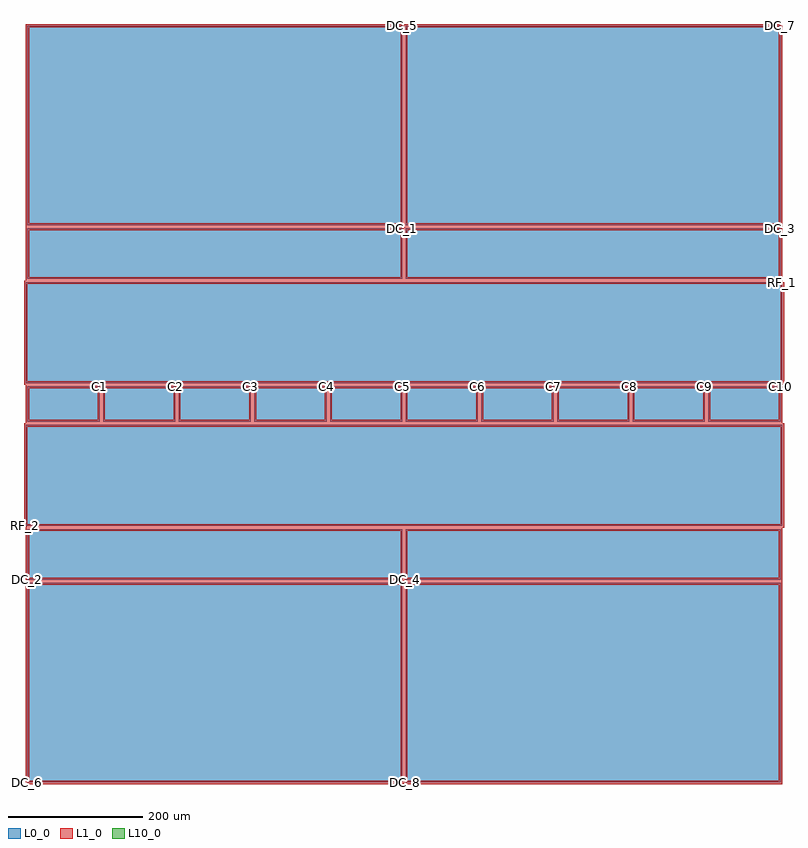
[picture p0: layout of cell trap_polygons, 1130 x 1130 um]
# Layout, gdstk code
import gdstk
lib = gdstk.Library(unit=1e-6, precision=1e-09)
def P(c, l, *ps):  # polygons
    for p in ps: c.add(gdstk.Polygon(p, *l))
L0_0 = (0, 0)
L1_0 = (1, 0)
L10_0 = (10, 0)

trap_polygons = lib.new_cell('trap_polygons')
P(trap_polygons, L0_0, [(2.5,-562.5),(2.5,-266.125),(560,-266.125),(560,-562.5),(2.5,-562.5)],
  [(560,562.5),(560,266.125),(2.5,266.125),(2.5,562.5),(560,562.5)],
  [(-560,-562.5),(-560,-266.125),(-2.5,-266.125),(-2.5,-562.5),(-560,-562.5)],
  [(-2.5,562.5),(-2.5,266.125),(-560,266.125),(-560,562.5),(-2.5,562.5)],
  [(2.5,-261.125),(2.5,-186.125),(560,-186.125),(560,-261.125),(2.5,-261.125)],
  [(560,261.125),(560,186.125),(2.5,186.125),(2.5,261.125),(560,261.125)],
  [(-560,-261.125),(-560,-186.125),(-2.5,-186.125),(-2.5,-261.125),(-560,-261.125)],
  [(-2.5,261.125),(-2.5,186.125),(-560,186.125),(-560,261.125),(-2.5,261.125)],
  [(560,26.125),(560,-26.125),(452.5,-26.125),(452.5,26.125),(560,26.125)],
  [(447.5,26.125),(447.5,-26.125),(340,-26.125),(340,26.125),(447.5,26.125)],
  [(335,26.125),(335,-26.125),(227.5,-26.125),(227.5,26.125),(335,26.125)],
  [(222.5,26.125),(222.5,-26.125),(115,-26.125),(115,26.125),(222.5,26.125)],
  [(110,26.125),(110,-26.125),(2.5,-26.125),(2.5,26.125),(110,26.125)],
  [(-2.5,26.125),(-2.5,-26.125),(-110,-26.125),(-110,26.125),(-2.5,26.125)],
  [(-115,26.125),(-115,-26.125),(-222.5,-26.125),(-222.5,26.125),(-115,26.125)],
  [(-227.5,26.125),(-227.5,-26.125),(-335,-26.125),(-335,26.125),(-227.5,26.125)],
  [(-340,26.125),(-340,-26.125),(-447.5,-26.125),(-447.5,26.125),(-340,26.125)],
  [(-452.5,26.125),(-452.5,-26.125),(-560,-26.125),(-560,26.125),(-452.5,26.125)],
  [(-562.5,-181.125),(-562.5,-31.125),(562.5,-31.125),(562.5,-181.125),(-562.5,-181.125)],
  [(562.5,181.125),(562.5,31.125),(-562.5,31.125),(-562.5,181.125),(562.5,181.125)])
P(trap_polygons, L1_0, [(0,-562.5),(5,-562.5),(5,-268.625),(557.5,-268.625),(557.5,-560),(2.5,-560),(2.5,-565),(562.5,-565),(562.5,-263.625),(0,-263.625)],
  [(562.5,562.5),(557.5,562.5),(557.5,268.625),(5,268.625),(5,560),(560,560),(560,565),(0,565),(0,263.625),(562.5,263.625)],
  [(-562.5,-562.5),(-557.5,-562.5),(-557.5,-268.625),(-5,-268.625),(-5,-560),(-560,-560),(-560,-565),(0,-565),(0,-263.625),(-562.5,-263.625)],
  [(0,562.5),(-5,562.5),(-5,268.625),(-557.5,268.625),(-557.5,560),(-2.5,560),(-2.5,565),(-562.5,565),(-562.5,263.625),(0,263.625)],
  [(0,-261.125),(5,-261.125),(5,-188.625),(557.5,-188.625),(557.5,-258.625),(2.5,-258.625),(2.5,-263.625),(562.5,-263.625),(562.5,-183.625),(0,-183.625)],
  [(562.5,261.125),(557.5,261.125),(557.5,188.625),(5,188.625),(5,258.625),(560,258.625),(560,263.625),(0,263.625),(0,183.625),(562.5,183.625)],
  [(-562.5,-261.125),(-557.5,-261.125),(-557.5,-188.625),(-5,-188.625),(-5,-258.625),(-560,-258.625),(-560,-263.625),(0,-263.625),(0,-183.625),(-562.5,-183.625)],
  [(0,261.125),(-5,261.125),(-5,188.625),(-557.5,188.625),(-557.5,258.625),(-2.5,258.625),(-2.5,263.625),(-562.5,263.625),(-562.5,183.625),(0,183.625)],
  [(562.5,26.125),(557.5,26.125),(557.5,-23.625),(455,-23.625),(455,23.625),(560,23.625),(560,28.625),(450,28.625),(450,-28.625),(562.5,-28.625)],
  [(450,26.125),(445,26.125),(445,-23.625),(342.5,-23.625),(342.5,23.625),(447.5,23.625),(447.5,28.625),(337.5,28.625),(337.5,-28.625),(450,-28.625)],
  [(337.5,26.125),(332.5,26.125),(332.5,-23.625),(230,-23.625),(230,23.625),(335,23.625),(335,28.625),(225,28.625),(225,-28.625),(337.5,-28.625)],
  [(225,26.125),(220,26.125),(220,-23.625),(117.5,-23.625),(117.5,23.625),(222.5,23.625),(222.5,28.625),(112.5,28.625),(112.5,-28.625),(225,-28.625)],
  [(112.5,26.125),(107.5,26.125),(107.5,-23.625),(5,-23.625),(5,23.625),(110,23.625),(110,28.625),(0,28.625),(0,-28.625),(112.5,-28.625)],
  [(0,26.125),(-5,26.125),(-5,-23.625),(-107.5,-23.625),(-107.5,23.625),(-2.5,23.625),(-2.5,28.625),(-112.5,28.625),(-112.5,-28.625),(0,-28.625)],
  [(-112.5,26.125),(-117.5,26.125),(-117.5,-23.625),(-220,-23.625),(-220,23.625),(-115,23.625),(-115,28.625),(-225,28.625),(-225,-28.625),(-112.5,-28.625)],
  [(-225,26.125),(-230,26.125),(-230,-23.625),(-332.5,-23.625),(-332.5,23.625),(-227.5,23.625),(-227.5,28.625),(-337.5,28.625),(-337.5,-28.625),(-225,-28.625)],
  [(-337.5,26.125),(-342.5,26.125),(-342.5,-23.625),(-445,-23.625),(-445,23.625),(-340,23.625),(-340,28.625),(-450,28.625),(-450,-28.625),(-337.5,-28.625)],
  [(-450,26.125),(-455,26.125),(-455,-23.625),(-557.5,-23.625),(-557.5,23.625),(-452.5,23.625),(-452.5,28.625),(-562.5,28.625),(-562.5,-28.625),(-450,-28.625)],
  [(-565,-181.125),(-560,-181.125),(-560,-33.625),(560,-33.625),(560,-178.625),(-562.5,-178.625),(-562.5,-183.625),(565,-183.625),(565,-28.625),(-565,-28.625)],
  [(565,181.125),(560,181.125),(560,33.625),(-560,33.625),(-560,178.625),(562.5,178.625),(562.5,183.625),(-565,183.625),(-565,28.625),(565,28.625)])
P(trap_polygons, L10_0, [(0,0),(0,0),(0,0),(0,0)])
trap_polygons.add(gdstk.Label('DC_8', (2.5,-562.5), layer=2, texttype=0))
trap_polygons.add(gdstk.Label('DC_7', (560,562.5), layer=2, texttype=0))
trap_polygons.add(gdstk.Label('DC_6', (-560,-562.5), layer=2, texttype=0))
trap_polygons.add(gdstk.Label('DC_5', (-2.5,562.5), layer=2, texttype=0))
trap_polygons.add(gdstk.Label('DC_4', (2.5,-261.125), layer=2, texttype=0))
trap_polygons.add(gdstk.Label('DC_3', (560,261.125), layer=2, texttype=0))
trap_polygons.add(gdstk.Label('DC_2', (-560,-261.125), layer=2, texttype=0))
trap_polygons.add(gdstk.Label('DC_1', (-2.5,261.125), layer=2, texttype=0))
trap_polygons.add(gdstk.Label('C10', (560,26.125), layer=2, texttype=0))
trap_polygons.add(gdstk.Label('C9', (447.5,26.125), layer=2, texttype=0))
trap_polygons.add(gdstk.Label('C8', (335,26.125), layer=2, texttype=0))
trap_polygons.add(gdstk.Label('C7', (222.5,26.125), layer=2, texttype=0))
trap_polygons.add(gdstk.Label('C6', (110,26.125), layer=2, texttype=0))
trap_polygons.add(gdstk.Label('C5', (-2.5,26.125), layer=2, texttype=0))
trap_polygons.add(gdstk.Label('C4', (-115,26.125), layer=2, texttype=0))
trap_polygons.add(gdstk.Label('C3', (-227.5,26.125), layer=2, texttype=0))
trap_polygons.add(gdstk.Label('C2', (-340,26.125), layer=2, texttype=0))
trap_polygons.add(gdstk.Label('C1', (-452.5,26.125), layer=2, texttype=0))
trap_polygons.add(gdstk.Label('RF_2', (-562.5,-181.125), layer=2, texttype=0))
trap_polygons.add(gdstk.Label('RF_1', (562.5,181.125), layer=2, texttype=0))

lib.write_gds('trap_polygons.gds')
